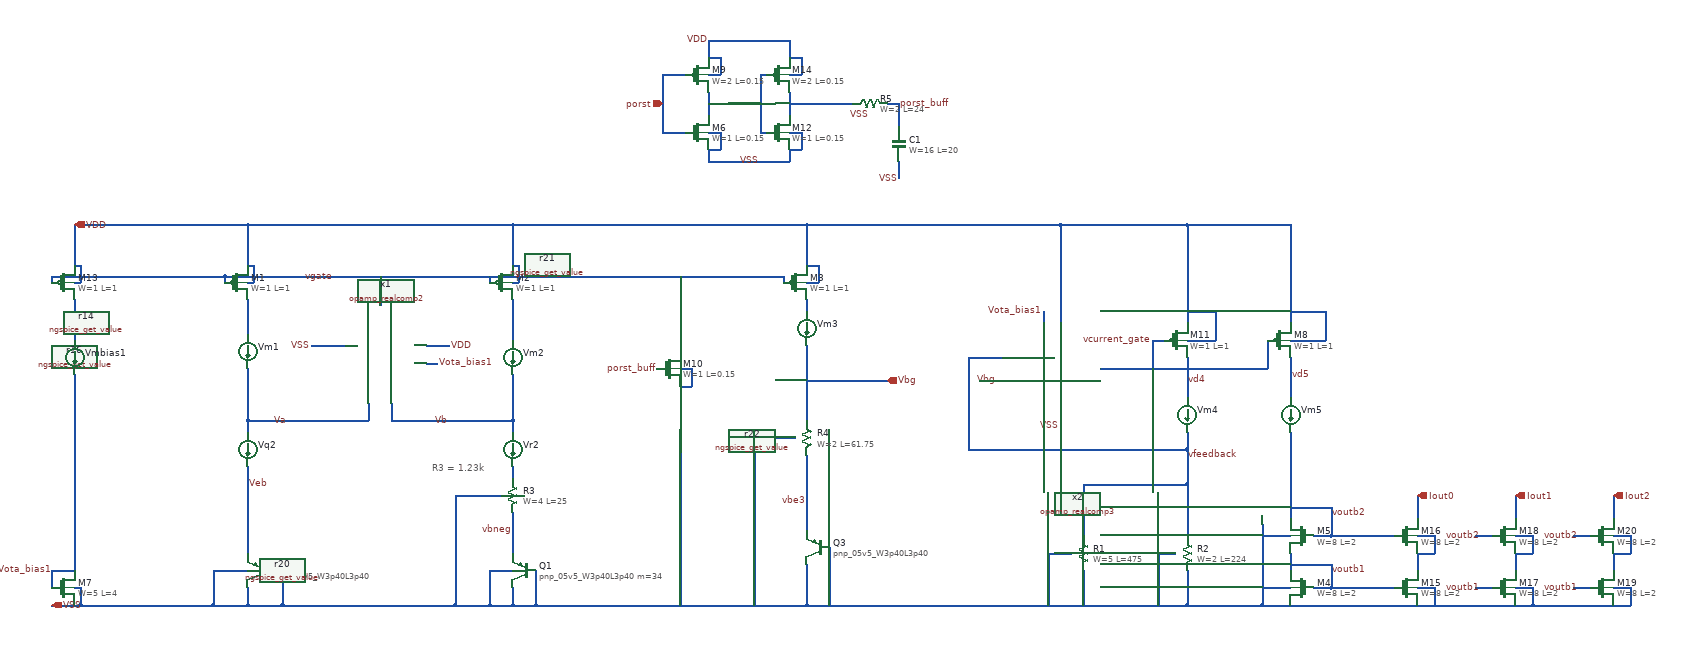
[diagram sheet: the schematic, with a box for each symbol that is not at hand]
v {xschem version=3.0.0 file_version=1.2 }
G {}
K {}
V {}
S {}
E {}
T {R3 = 1.23k} -650 -260 0 0 0.4 0.4 {}
N -970 -40 -970 -10 { lab=VSS}
N -1030 -70 -970 -70 { lab=VSS}
N -1030 -70 -1030 -10 { lab=VSS}
N -970 -670 -750 -670 { lab=VDD}
N -510 -670 -310 -670 { lab=VDD}
N -510 -330 -510 -310 { lab=Vb}
N -510 -410 -510 -330 { lab=Vb}
N 0 -460 0 -330 { lab=Vbg}
N -510 -250 -510 -230 { lab=#net1}
N -510 -540 -510 -470 { lab=#net2}
N -510 -170 -510 -100 { lab=vbneg}
N -470 -70 -470 -10 { lab=VSS}
N -510 -40 -510 -10 { lab=VSS}
N -550 -70 -510 -70 { lab=VSS}
N -550 -70 -550 -10 { lab=VSS}
N -930 -70 -910 -70 { lab=VSS}
N -910 -70 -910 -10 { lab=VSS}
N -610 -200 -530 -200 { lab=VSS}
N -610 -200 -610 -10 { lab=VSS}
N -970 -250 -970 -100 { lab=Veb}
N -620 -330 -510 -330 { lab=Vb}
N -1270 -40 -1260 -40 { lab=VSS}
N -1310 -70 -1310 -40 { lab=Vota_bias1}
N -1310 -70 -1270 -70 { lab=Vota_bias1}
N -1260 -40 -1260 -10 { lab=VSS}
N -120 -670 0 -670 { lab=VDD}
N -510 -670 -510 -600 { lab=VDD}
N -120 -10 0 -10 { lab=VSS}
N -970 -330 -970 -310 { lab=Va}
N -550 -580 -550 -570 { lab=vgate}
N -1010 -580 -1010 -570 { lab=vgate}
N -970 -540 -970 -480 { lab=#net3}
N -1270 -570 -1260 -570 { lab=VDD}
N -1260 -600 -1260 -570 { lab=VDD}
N -1270 -600 -1260 -600 { lab=VDD}
N -970 -570 -960 -570 { lab=VDD}
N -960 -600 -960 -570 { lab=VDD}
N -970 -600 -960 -600 { lab=VDD}
N -970 -670 -970 -600 { lab=VDD}
N -510 -570 -500 -570 { lab=VDD}
N -500 -600 -500 -570 { lab=VDD}
N -510 -600 -500 -600 { lab=VDD}
N -1230 -670 -970 -670 { lab=VDD}
N -70 -580 -40 -580 { lab=vgate}
N -1310 -580 -1310 -570 { lab=vgate}
N -1270 -670 -1270 -600 { lab=VDD}
N -1270 -350 -1270 -70 { lab=Vota_bias1}
N -970 -330 -900 -330 { lab=Va}
N -1030 -10 -970 -10 { lab=VSS}
N -1100 -10 -1030 -10 { lab=VSS}
N -1220 -10 -1100 -10 { lab=VSS}
N -470 -10 -380 -10 { lab=VSS}
N -510 -10 -470 -10 { lab=VSS}
N -550 -10 -510 -10 { lab=VSS}
N -610 -10 -550 -10 { lab=VSS}
N -970 -10 -910 -10 { lab=VSS}
N -910 -10 -850 -10 { lab=VSS}
N 0 -270 0 -250 { lab=vbe3}
N -310 -670 -120 -670 { lab=VDD}
N -1010 -580 -790 -580 { lab=vgate}
N -790 -580 -310 -580 { lab=vgate}
N -970 -420 -970 -330 { lab=Va}
N -1270 -670 -1230 -670 { lab=VDD}
N -1260 -10 -1220 -10 { lab=VSS}
N -1170 -580 -1010 -580 { lab=vgate}
N -1310 -580 -1170 -580 { lab=vgate}
N 0 -670 300 -670 {
lab=VDD}
N -720 -330 -620 -330 {
lab=Vb}
N -720 -360 -720 -330 {
lab=Vb}
N -900 -330 -760 -330 {
lab=Va}
N -760 -360 -760 -330 {
lab=Va}
N -740 -580 -740 -530 {
lab=vgate}
N -750 -670 -510 -670 {
lab=VDD}
N -310 -580 -70 -580 {
lab=vgate}
N -850 -10 -610 -10 {
lab=VSS}
N -380 -10 -120 -10 {
lab=VSS}
N -860 -460 -800 -460 {
lab=VSS}
N -660 -460 -620 -460 {
lab=VDD}
N -660 -430 -640 -430 {
lab=Vota_bias1}
N 0 -250 0 -140 {
lab=vbe3}
N 0 -80 0 -10 {
lab=VSS}
N 40 -110 40 -10 {
lab=VSS}
N 0 -400 140 -400 {
lab=Vbg}
N -1270 -540 -1270 -470 {
lab=#net4}
N -1270 -410 -1270 -350 {
lab=Vota_bias1}
N -90 -300 -20 -300 {
lab=VSS}
N -90 -300 -90 -10 {
lab=VSS}
N -40 -580 -40 -570 {
lab=vgate}
N 0 -670 0 -600 {
lab=VDD}
N 0 -540 0 -520 {
lab=#net5}
N -1270 -10 -1260 -10 {
lab=VSS}
N -0 -570 20 -570 {
lab=VDD}
N 20 -600 20 -570 {
lab=VDD}
N 0 -600 20 -600 {
lab=VDD}
N -220 -390 -220 -10 {
lab=VSS}
N -220 -420 -210 -420 { lab=VSS}
N 410 -670 440 -670 {
lab=VDD}
N 440 -670 440 -500 {
lab=VDD}
N 280 -440 340 -440 {
lab=vfeedback}
N 560 -420 620 -420 {
lab=vcurrent_gate}
N 440 -670 660 -670 {
lab=VDD}
N 440 -360 440 -320 {
lab=VSS}
N 660 -390 660 -370 {
lab=vd4}
N 660 -310 660 -280 {
lab=vfeedback}
N 660 -440 660 -390 {
lab=vd4}
N 600 -470 600 -420 {
lab=vcurrent_gate}
N 600 -470 620 -470 {
lab=vcurrent_gate}
N 660 -670 660 -500 {
lab=VDD}
N 840 -390 840 -370 {
lab=vd5}
N 840 -440 840 -390 {
lab=vd5}
N 620 -420 780 -420 {
lab=vcurrent_gate}
N 840 -670 840 -500 {
lab=VDD}
N 660 -670 840 -670 {
lab=VDD}
N 790 -150 790 -10 {
lab=VSS}
N 660 -470 710 -470 {
lab=VDD}
N 710 -520 710 -470 {
lab=VDD}
N 660 -520 710 -520 {
lab=VDD}
N 840 -470 900 -470 {
lab=VDD}
N 900 -520 900 -470 {
lab=VDD}
N 840 -520 900 -520 {
lab=VDD}
N 300 -400 340 -400 {
lab=Vbg}
N 300 -670 410 -670 {
lab=VDD}
N 370 -10 660 -10 {
lab=VSS}
N 840 -10 910 -10 {
lab=VSS}
N 410 -520 410 -500 {
lab=Vota_bias1}
N 660 -280 660 -250 {
lab=vfeedback}
N 480 -220 660 -220 {
lab=vfeedback}
N 480 -220 480 -130 {
lab=vfeedback}
N 480 -70 480 -20 {
lab=VSS}
N 420 -100 460 -100 {
lab=VSS}
N 420 -100 420 -20 {
lab=VSS}
N 660 -250 660 -220 {
lab=vfeedback}
N 420 -20 420 -10 {
lab=VSS}
N 480 -20 480 -10 {
lab=VSS}
N 610 -20 610 -10 {
lab=VSS}
N 840 -100 840 -70 {
lab=voutb1}
N 840 -200 840 -160 {
lab=voutb2}
N 840 -310 840 -260 {
lab=voutb2}
N 880 -40 910 -40 {
lab=voutb1}
N 910 -80 910 -40 {
lab=voutb1}
N 910 -180 910 -130 {
lab=voutb2}
N 840 -180 910 -180 {
lab=voutb2}
N 790 -130 840 -130 {
lab=VSS}
N 790 -40 840 -40 {
lab=VSS}
N 880 -130 910 -130 {
lab=voutb2}
N 840 -80 910 -80 {
lab=voutb1}
N 660 -10 790 -10 {
lab=VSS}
N 790 -10 840 -10 {
lab=VSS}
N 660 -220 660 -160 {
lab=vfeedback}
N 610 -100 640 -100 {
lab=VSS}
N 660 -70 660 -10 {
lab=VSS}
N 610 -90 610 -20 {
lab=VSS}
N 660 -160 660 -130 {
lab=vfeedback}
N 0 -10 370 -10 {
lab=VSS}
N -220 -500 -220 -450 {
lab=vgate}
N -220 -580 -220 -500 {
lab=vgate}
N 280 -310 280 -280 {
lab=vfeedback}
N 280 -400 280 -310 {
lab=vfeedback}
N 280 -440 280 -400 {
lab=vfeedback}
N 510 -420 560 -420 {
lab=vcurrent_gate}
N 780 -420 800 -420 {
lab=vcurrent_gate}
N 800 -470 800 -420 {
lab=vcurrent_gate}
N -170 -900 -170 -860 {
lab=#net6}
N -250 -830 -210 -830 {
lab=porst}
N -250 -930 -250 -830 {
lab=porst}
N -250 -930 -210 -930 {
lab=porst}
N -170 -990 -170 -960 {
lab=VDD}
N -30 -900 -30 -860 {
lab=#net7}
N -30 -990 -30 -960 {
lab=VDD}
N -80 -830 -70 -830 {
lab=#net6}
N -80 -930 -80 -830 {
lab=#net6}
N -80 -930 -70 -930 {
lab=#net6}
N -170 -880 -80 -880 {
lab=#net6}
N -170 -990 -30 -990 {
lab=VDD}
N -170 -800 -170 -780 {
lab=VSS}
N -170 -780 -30 -780 {
lab=VSS}
N -30 -800 -30 -780 {
lab=VSS}
N -170 -930 -150 -930 {
lab=VDD}
N -150 -960 -150 -930 {
lab=VDD}
N -170 -960 -150 -960 {
lab=VDD}
N -30 -930 -10 -930 {
lab=VDD}
N -10 -960 -10 -930 {
lab=VDD}
N -30 -960 -10 -960 {
lab=VDD}
N -170 -830 -150 -830 {
lab=VSS}
N -150 -830 -150 -800 {
lab=VSS}
N -170 -800 -150 -800 {
lab=VSS}
N -30 -830 -10 -830 {
lab=VSS}
N -10 -830 -10 -800 {
lab=VSS}
N -30 -800 -10 -800 {
lab=VSS}
N -210 -420 -200 -420 {
lab=VSS}
N -200 -420 -200 -390 {
lab=VSS}
N -220 -390 -200 -390 {
lab=VSS}
N 160 -880 160 -840 {
lab=porst_buff}
N 140 -880 160 -880 {
lab=porst_buff}
N -30 -880 80 -880 {
lab=#net7}
N 160 -780 160 -750 {
lab=VSS}
N 840 -260 840 -200 {
lab=voutb2}
N 1060 -100 1060 -70 {
lab=#net8}
N 910 -10 1060 -10 {
lab=VSS}
N 1060 -10 1230 -10 {
lab=VSS}
N 1230 -100 1230 -70 {
lab=#net9}
N 1060 -200 1060 -160 {
lab=Iout0}
N 1230 -200 1230 -160 {
lab=Iout1}
N 910 -40 1020 -40 {
lab=voutb1}
N 910 -130 1020 -130 {
lab=voutb2}
N 1160 -40 1190 -40 {
lab=voutb1}
N 1160 -130 1190 -130 {
lab=voutb2}
N 1060 -130 1090 -130 {
lab=#net8}
N 1090 -130 1090 -100 {
lab=#net8}
N 1060 -100 1090 -100 {
lab=#net8}
N 1060 -40 1090 -40 {
lab=VSS}
N 1090 -40 1090 -10 {
lab=VSS}
N 1230 -130 1260 -130 {
lab=#net9}
N 1260 -130 1260 -100 {
lab=#net9}
N 1230 -100 1260 -100 {
lab=#net9}
N 1230 -40 1260 -40 {
lab=VSS}
N 1260 -40 1260 -10 {
lab=VSS}
N 1230 -10 1260 -10 {
lab=VSS}
N 280 -280 660 -280 {
lab=vfeedback}
N -1310 -10 -1270 -10 {
lab=VSS}
N 610 -100 610 -90 {
lab=VSS}
N 1400 -100 1400 -70 {
lab=#net10}
N 1400 -200 1400 -160 {
lab=Iout2}
N 1330 -40 1360 -40 {
lab=voutb1}
N 1330 -130 1360 -130 {
lab=voutb2}
N 1400 -130 1430 -130 {
lab=#net10}
N 1430 -130 1430 -100 {
lab=#net10}
N 1400 -100 1430 -100 {
lab=#net10}
N 1400 -40 1430 -40 {
lab=VSS}
N 1430 -40 1430 -10 {
lab=VSS}
N 1400 -10 1430 -10 {
lab=VSS}
N 1260 -10 1400 -10 {
lab=VSS}
C {sky130_fd_pr/pnp_05v5.sym} -950 -70 0 1 {name=Q2
model=pnp_05v5_W3p40L3p40
spiceprefix=X
}
C {devices/lab_pin.sym} -900 -330 3 0 {name=l5 lab=Va}
C {devices/lab_pin.sym} -620 -330 3 0 {name=l6 lab=Vb}
C {devices/ammeter.sym} -510 -280 0 0 {name=Vr2 current=4.3334e-06}
C {devices/ammeter.sym} -970 -450 0 0 {name=Vm1 current=1.0057e-05}
C {devices/ammeter.sym} -510 -440 0 0 {name=Vm2 current=1.0057e-05}
C {devices/ammeter.sym} 0 -490 0 0 {name=Vm3 current=1.0239e-05}
C {devices/ammeter.sym} -970 -280 0 0 {name=Vq2 current=4.3346e-06}
C {sky130_fd_pr/pnp_05v5.sym} -490 -70 0 1 {name=Q1
model="pnp_05v5_W3p40L3p40 m=34"
spiceprefix=X
}
C {devices/lab_pin.sym} -510 -140 0 0 {name=l4 lab=vbneg}
C {devices/lab_pin.sym} -970 -220 2 0 {name=l10 lab=Veb}
C {devices/lab_wire.sym} -820 -580 0 0 {name=l11 lab=vgate}
C {sky130_fd_pr/nfet_01v8_lvt.sym} -1290 -40 0 0 {name=M7
L=4
W=5
nf=1
mult=1
ad="'int((nf+1)/2) * W/nf * 0.29'" 
pd="'2*int((nf+1)/2) * (W/nf + 0.29)'"
as="'int((nf+2)/2) * W/nf * 0.29'" 
ps="'2*int((nf+2)/2) * (W/nf + 0.29)'"
nrd="'0.29 / W'" nrs="'0.29 / W'"
sa=0 sb=0 sd=0
model=nfet_01v8_lvt
spiceprefix=X
}
C {sky130_fd_pr/pfet_01v8_lvt.sym} -1290 -570 0 0 {name=M13
L=1
W=1
nf=1
mult=10
ad="'int((nf+1)/2) * W/nf * 0.29'" 
pd="'2*int((nf+1)/2) * (W/nf + 0.29)'"
as="'int((nf+2)/2) * W/nf * 0.29'" 
ps="'2*int((nf+2)/2) * (W/nf + 0.29)'"
nrd="'0.29 / W'" nrs="'0.29 / W'"
sa=0 sb=0 sd=0
model=pfet_01v8_lvt
spiceprefix=X
}
C {sky130_fd_pr/pfet_01v8_lvt.sym} -990 -570 0 0 {name=M1
L=1
W=1
nf=1
mult=28
ad="'int((nf+1)/2) * W/nf * 0.29'" 
pd="'2*int((nf+1)/2) * (W/nf + 0.29)'"
as="'int((nf+2)/2) * W/nf * 0.29'" 
ps="'2*int((nf+2)/2) * (W/nf + 0.29)'"
nrd="'0.29 / W'" nrs="'0.29 / W'"
sa=0 sb=0 sd=0
model=pfet_01v8_lvt
spiceprefix=X
}
C {sky130_fd_pr/pfet_01v8_lvt.sym} -530 -570 0 0 {name=M2
L=1
W=1
nf=1
mult=28
ad="'int((nf+1)/2) * W/nf * 0.29'" 
pd="'2*int((nf+1)/2) * (W/nf + 0.29)'"
as="'int((nf+2)/2) * W/nf * 0.29'" 
ps="'2*int((nf+2)/2) * (W/nf + 0.29)'"
nrd="'0.29 / W'" nrs="'0.29 / W'"
sa=0 sb=0 sd=0
model=pfet_01v8_lvt
spiceprefix=X
}
C {sky130_fd_pr/pfet_01v8_lvt.sym} -20 -570 0 0 {name=M3
L=1
W=1
nf=1
mult=28
ad="'int((nf+1)/2) * W/nf * 0.29'" 
pd="'2*int((nf+1)/2) * (W/nf + 0.29)'"
as="'int((nf+2)/2) * W/nf * 0.29'" 
ps="'2*int((nf+2)/2) * (W/nf + 0.29)'"
nrd="'0.29 / W'" nrs="'0.29 / W'"
sa=0 sb=0 sd=0
model=pfet_01v8_lvt
spiceprefix=X
}
C {devices/ngspice_probe.sym} -970 -330 0 0 {name=r1}
C {devices/ngspice_probe.sym} -510 -330 0 0 {name=r2}
C {devices/ngspice_probe.sym} -1270 -320 0 0 {name=r3}
C {devices/ngspice_probe.sym} -820 -580 0 0 {name=r5}
C {devices/ngspice_probe.sym} -510 -140 0 0 {name=r9}
C {devices/ngspice_get_value.sym} -1270 -440 0 0 {name=r16 node=i(@m.xm13.msky130_fd_pr__pfet_01v8_lvt[id])
descr="I="}
C {devices/ngspice_get_value.sym} -1250 -500 0 0 {name=r14 node=@m.xm13.msky130_fd_pr__pfet_01v8_lvt[gm]
descr="gm="}
C {devices/ngspice_get_value.sym} -950 -500 0 0 {name=r20 node=@m.xm1.msky130_fd_pr__pfet_01v8_lvt[gm]
descr="gm="}
C {devices/ngspice_get_value.sym} -540 -500 0 1 {name=r21 node=@m.xm2.msky130_fd_pr__pfet_01v8_lvt[gm]
descr="gm="}
C {devices/ngspice_get_value.sym} 10 -530 0 0 {name=r22 node=@m.xm3.msky130_fd_pr__pfet_01v8_lvt[gm]
descr="gm="}
C {devices/lab_wire.sym} -620 -460 0 1 {name=l14 lab=VDD}
C {devices/lab_pin.sym} 0 -190 0 0 {name=l15 lab=vbe3}
C {sky130_fd_pr/pnp_05v5.sym} 20 -110 0 1 {name=Q3
model=pnp_05v5_W3p40L3p40
*model="pnp_05v5_W3p40L3p40 m=1"
spiceprefix=X
}
C {devices/lab_pin.sym} -1310 -70 2 1 {name=l2 lab=Vota_bias1}
C {devices/lab_pin.sym} -640 -430 2 0 {name=l18 lab=Vota_bias1}
C {devices/ammeter.sym} -1270 -440 0 0 {name=Vmbias1 current=1.0057e-05}
C {sky130_fd_pr/res_high_po.sym} -510 -200 0 0 {name=R3
W=4
L=25
model=res_high_po
spiceprefix=X
mult=1}
C {sky130_fd_pr/res_high_po.sym} 0 -300 0 0 {name=R4
W=2
L=61.75
model=res_high_po
spiceprefix=X
mult=1}
C {sky130_fd_pr/nfet_01v8_lvt.sym} -240 -420 0 0 {name=M10
L=0.15
W=1
nf=1
mult=1
ad="'int((nf+1)/2) * W/nf * 0.29'" 
pd="'2*int((nf+1)/2) * (W/nf + 0.29)'"
as="'int((nf+2)/2) * W/nf * 0.29'" 
ps="'2*int((nf+2)/2) * (W/nf + 0.29)'"
nrd="'0.29 / W'" nrs="'0.29 / W'"
sa=0 sb=0 sd=0
model=nfet_01v8_lvt
spiceprefix=X
}
C {devices/lab_pin.sym} -260 -420 0 0 {name=l26 lab=porst_buff}
C {sky130_fd_pr/pfet_01v8_lvt.sym} 640 -470 0 0 {name=M11
L=1
W=1
nf=1
mult=5
ad="'int((nf+1)/2) * W/nf * 0.29'" 
pd="'2*int((nf+1)/2) * (W/nf + 0.29)'"
as="'int((nf+2)/2) * W/nf * 0.29'" 
ps="'2*int((nf+2)/2) * (W/nf + 0.29)'"
nrd="'0.29 / W'" nrs="'0.29 / W'"
sa=0 sb=0 sd=0
model=pfet_01v8_lvt
spiceprefix=X
}
C {devices/ammeter.sym} 660 -340 0 0 {name=Vm4 current=1.0239e-05}
C {sky130_fd_pr/pfet_01v8_lvt.sym} 820 -470 0 0 {name=M8
L=1
W=1
nf=1
mult=5
ad="'int((nf+1)/2) * W/nf * 0.29'" 
pd="'2*int((nf+1)/2) * (W/nf + 0.29)'"
as="'int((nf+2)/2) * W/nf * 0.29'" 
ps="'2*int((nf+2)/2) * (W/nf + 0.29)'"
nrd="'0.29 / W'" nrs="'0.29 / W'"
sa=0 sb=0 sd=0
model=pfet_01v8_lvt
spiceprefix=X
}
C {devices/ammeter.sym} 840 -340 0 0 {name=Vm5 current=1.0239e-05}
C {sky130_fd_pr/nfet_01v8_lvt.sym} 860 -40 0 1 {name=M4
L=2
W=8
nf=1
mult=8
ad="'int((nf+1)/2) * W/nf * 0.29'" 
pd="'2*int((nf+1)/2) * (W/nf + 0.29)'"
as="'int((nf+2)/2) * W/nf * 0.29'" 
ps="'2*int((nf+2)/2) * (W/nf + 0.29)'"
nrd="'0.29 / W'" nrs="'0.29 / W'"
sa=0 sb=0 sd=0
model=nfet_01v8_lvt
spiceprefix=X
}
C {devices/lab_pin.sym} 840 -410 0 1 {name=l24 lab=vd5}
C {devices/lab_pin.sym} 660 -400 0 1 {name=l25 lab=vd4}
C {devices/lab_pin.sym} 410 -520 2 1 {name=l19 lab=Vota_bias1}
C {sky130_fd_pr/nfet_01v8_lvt.sym} 860 -130 0 1 {name=M5
L=2
W=8
nf=1
mult=8
ad="'int((nf+1)/2) * W/nf * 0.29'" 
pd="'2*int((nf+1)/2) * (W/nf + 0.29)'"
as="'int((nf+2)/2) * W/nf * 0.29'" 
ps="'2*int((nf+2)/2) * (W/nf + 0.29)'"
nrd="'0.29 / W'" nrs="'0.29 / W'"
sa=0 sb=0 sd=0
model=nfet_01v8_lvt
spiceprefix=X
}
C {lab_wire.sym} 330 -400 0 0 {name=l7 sig_type=std_logic lab=Vbg}
C {devices/lab_pin.sym} 600 -470 0 0 {name=l21 lab=vcurrent_gate}
C {devices/lab_pin.sym} 660 -270 0 1 {name=l29 lab=vfeedback}
C {sky130_fd_pr/res_high_po.sym} 660 -100 0 0 {name=R2
W=2
L=224
model=res_high_po
spiceprefix=X
mult=1}
C {sky130_fd_pr/res_high_po.sym} 480 -100 0 0 {name=R1
W=5
L=475
model=res_xhigh_po
spiceprefix=X
mult=1}
C {sky130_fd_pr/nfet_01v8.sym} -190 -830 0 0 {name=M6
L=0.15
W=1
nf=1 
mult=1
ad="'int((nf+1)/2) * W/nf * 0.29'" 
pd="'2*int((nf+1)/2) * (W/nf + 0.29)'"
as="'int((nf+2)/2) * W/nf * 0.29'" 
ps="'2*int((nf+2)/2) * (W/nf + 0.29)'"
nrd="'0.29 / W'" nrs="'0.29 / W'"
sa=0 sb=0 sd=0
model=nfet_01v8
spiceprefix=X
}
C {sky130_fd_pr/pfet_01v8.sym} -190 -930 0 0 {name=M9
L=0.15
W=2
nf=1
mult=1
ad="'int((nf+1)/2) * W/nf * 0.29'" 
pd="'2*int((nf+1)/2) * (W/nf + 0.29)'"
as="'int((nf+2)/2) * W/nf * 0.29'" 
ps="'2*int((nf+2)/2) * (W/nf + 0.29)'"
nrd="'0.29 / W'" nrs="'0.29 / W'"
sa=0 sb=0 sd=0
model=pfet_01v8
spiceprefix=X
}
C {sky130_fd_pr/nfet_01v8.sym} -50 -830 0 0 {name=M12
L=0.15
W=1
nf=1 
mult=1
ad="'int((nf+1)/2) * W/nf * 0.29'" 
pd="'2*int((nf+1)/2) * (W/nf + 0.29)'"
as="'int((nf+2)/2) * W/nf * 0.29'" 
ps="'2*int((nf+2)/2) * (W/nf + 0.29)'"
nrd="'0.29 / W'" nrs="'0.29 / W'"
sa=0 sb=0 sd=0
model=nfet_01v8
spiceprefix=X
}
C {sky130_fd_pr/pfet_01v8.sym} -50 -930 0 0 {name=M14
L=0.15
W=2
nf=1
mult=1
ad="'int((nf+1)/2) * W/nf * 0.29'" 
pd="'2*int((nf+1)/2) * (W/nf + 0.29)'"
as="'int((nf+2)/2) * W/nf * 0.29'" 
ps="'2*int((nf+2)/2) * (W/nf + 0.29)'"
nrd="'0.29 / W'" nrs="'0.29 / W'"
sa=0 sb=0 sd=0
model=pfet_01v8
spiceprefix=X
}
C {lab_wire.sym} -170 -990 0 0 {name=l28 sig_type=std_logic lab=VDD}
C {devices/lab_pin.sym} 160 -880 0 1 {name=l31 lab=porst_buff}
C {devices/lab_pin.sym} 910 -70 0 1 {name=l34 lab=voutb1}
C {devices/lab_pin.sym} 910 -170 0 1 {name=l35 lab=voutb2}
C {sky130_fd_pr/nfet_01v8_lvt.sym} 1040 -40 0 0 {name=M15
L=2
W=8
nf=1
mult=8
ad="'int((nf+1)/2) * W/nf * 0.29'" 
pd="'2*int((nf+1)/2) * (W/nf + 0.29)'"
as="'int((nf+2)/2) * W/nf * 0.29'" 
ps="'2*int((nf+2)/2) * (W/nf + 0.29)'"
nrd="'0.29 / W'" nrs="'0.29 / W'"
sa=0 sb=0 sd=0
model=nfet_01v8_lvt
spiceprefix=X
}
C {sky130_fd_pr/nfet_01v8_lvt.sym} 1040 -130 0 0 {name=M16
L=2
W=8
nf=1
mult=8
ad="'int((nf+1)/2) * W/nf * 0.29'" 
pd="'2*int((nf+1)/2) * (W/nf + 0.29)'"
as="'int((nf+2)/2) * W/nf * 0.29'" 
ps="'2*int((nf+2)/2) * (W/nf + 0.29)'"
nrd="'0.29 / W'" nrs="'0.29 / W'"
sa=0 sb=0 sd=0
model=nfet_01v8_lvt
spiceprefix=X
}
C {sky130_fd_pr/nfet_01v8_lvt.sym} 1210 -40 0 0 {name=M17
L=2
W=8
nf=1
mult=8
ad="'int((nf+1)/2) * W/nf * 0.29'" 
pd="'2*int((nf+1)/2) * (W/nf + 0.29)'"
as="'int((nf+2)/2) * W/nf * 0.29'" 
ps="'2*int((nf+2)/2) * (W/nf + 0.29)'"
nrd="'0.29 / W'" nrs="'0.29 / W'"
sa=0 sb=0 sd=0
model=nfet_01v8_lvt
spiceprefix=X
}
C {sky130_fd_pr/nfet_01v8_lvt.sym} 1210 -130 0 0 {name=M18
L=2
W=8
nf=1
mult=8
ad="'int((nf+1)/2) * W/nf * 0.29'" 
pd="'2*int((nf+1)/2) * (W/nf + 0.29)'"
as="'int((nf+2)/2) * W/nf * 0.29'" 
ps="'2*int((nf+2)/2) * (W/nf + 0.29)'"
nrd="'0.29 / W'" nrs="'0.29 / W'"
sa=0 sb=0 sd=0
model=nfet_01v8_lvt
spiceprefix=X
}
C {opin.sym} 1060 -200 0 0 {name=p1 lab=Iout0}
C {devices/lab_pin.sym} 1170 -40 0 0 {name=l36 lab=voutb1}
C {devices/lab_pin.sym} 1170 -130 0 0 {name=l37 lab=voutb2}
C {sky130_fd_pr/cap_mim_m3_1.sym} 160 -810 0 0 {name=C1 model=cap_mim_m3_1 W=16 L=20 MF=1 spiceprefix=X}
C {sky130_fd_pr/res_high_po.sym} 110 -880 3 0 {name=R5
W=2
L=24
model=res_high_po
spiceprefix=X
mult=1}
C {iopin.sym} -1270 -670 0 1 {name=p2 lab=VDD}
C {iopin.sym} -1310 -10 0 1 {name=p3 lab=VSS}
C {devices/lab_pin.sym} -80 -780 3 0 {name=l1 lab=VSS}
C {devices/lab_pin.sym} 160 -750 3 0 {name=l16 lab=VSS}
C {devices/lab_pin.sym} 110 -860 3 0 {name=l17 lab=VSS}
C {devices/lab_pin.sym} -860 -460 0 0 {name=l3 lab=VSS}
C {devices/lab_pin.sym} 440 -320 0 0 {name=l9 lab=VSS}
C {opin.sym} 1230 -200 0 0 {name=p4 lab=Iout1}
C {sky130_fd_pr/nfet_01v8_lvt.sym} 1380 -40 0 0 {name=M19
L=2
W=8
nf=1
mult=8
ad="'int((nf+1)/2) * W/nf * 0.29'" 
pd="'2*int((nf+1)/2) * (W/nf + 0.29)'"
as="'int((nf+2)/2) * W/nf * 0.29'" 
ps="'2*int((nf+2)/2) * (W/nf + 0.29)'"
nrd="'0.29 / W'" nrs="'0.29 / W'"
sa=0 sb=0 sd=0
model=nfet_01v8_lvt
spiceprefix=X
}
C {sky130_fd_pr/nfet_01v8_lvt.sym} 1380 -130 0 0 {name=M20
L=2
W=8
nf=1
mult=8
ad="'int((nf+1)/2) * W/nf * 0.29'" 
pd="'2*int((nf+1)/2) * (W/nf + 0.29)'"
as="'int((nf+2)/2) * W/nf * 0.29'" 
ps="'2*int((nf+2)/2) * (W/nf + 0.29)'"
nrd="'0.29 / W'" nrs="'0.29 / W'"
sa=0 sb=0 sd=0
model=nfet_01v8_lvt
spiceprefix=X
}
C {devices/lab_pin.sym} 1340 -40 0 0 {name=l13 lab=voutb1}
C {devices/lab_pin.sym} 1340 -130 0 0 {name=l20 lab=voutb2}
C {opin.sym} 1400 -200 0 0 {name=p5 lab=Iout2}
C {ipin.sym} -250 -880 0 0 {name=p6 lab=porst}
C {opin.sym} 140 -400 0 0 {name=p7 lab=Vbg}
C {opamp/opamp_realcomp2.sym} -740 -460 1 1 {name=x1}
C {opamp/opamp_realcomp3.sym} 440 -420 0 0 {name=x2}
